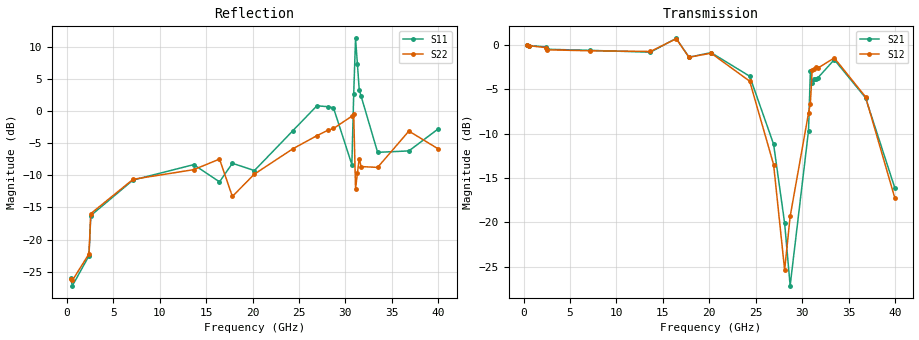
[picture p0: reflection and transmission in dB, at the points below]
! Network Analyzer HP8722ES.07.66: Jul 25, 2000 Serial No. US39175408
! 27 Oct 2004  13:03:41
! Frequency  S11  S21  S12  S22
# HZ  S  DB R  50
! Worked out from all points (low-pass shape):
!   201 points, 400 MHz to 40 GHz, reference 50 ohm
!   highest |S21| = 0.76 dB at 16.44 GHz (marker M1); lowest = -27.1 dB at 28.71 GHz (marker M2)
!   |S21| within 3 dB of the highest: start of sweep to 22.83 GHz; 32.62 GHz to 34.68 GHz (2.058 GHz wide, 6.11 % of centre)
!   lowest |S11| = -27.2 dB at 598 MHz (marker M3), VSWR 1.09, Z = 50.5 - j4.38 ohm
!   |S11| at or under -10 dB: start of sweep to 8.362 GHz; 18.2 GHz to 19.98 GHz (1.779 GHz wide, 9.32 % of centre); 34.47 GHz to 35.31 GHz (841.7 MHz wide, 2.41 % of centre) (the widest 3 of 4)
!   |S22| runs from -26.9 to -0.5 dB; largest |S21 - S12| = 0.27
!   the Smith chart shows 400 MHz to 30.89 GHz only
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4e8  -26.02 -92.3  -0.04 -0.1  -0.03 0.4  -26.09 -90.7
5.98e8  -27.16 -81.1  -0.06 -1.0  -0.07 -0.7  -26.33 -91.0
2.38e9  -22.52 -76.8  -0.20 -9.9  -0.28 -9.8  -22.22 -102.8
2.578e9  -16.26 -78.7  -0.47 -6.7  -0.53 -6.3  -15.96 -90.5
7.132e9  -10.74 -89.8  -0.59 -21.3  -0.64 -22.2  -10.63 -133.1
1.3666e10  -8.35 -77.1  -0.80 -38.7  -0.72 -39.8  -9.13 175.7
1.6438e10  -11.03 -67.2  0.76 -51.1  0.72 -52.4  -7.49 123.7
1.7824e10  -8.14 -51.1  -1.36 -57.5  -1.37 -59.2  -13.29 76.9
2.02e10  -9.27 -0.1  -0.85 -70.4  -0.91 -72.0  -9.82 31.0
2.4358e10  -3.05 18.0  -3.51 -110.5  -4.07 -116.2  -5.87 -55.1
2.6932e10  0.80 1.3  -11.18 -118.6  -13.48 -119.9  -3.85 -70.3
2.812e10  0.65 -10.9  -20.08 -116.8  -25.35 -75.8  -3.00 -89.1
2.8714e10  0.47 -16.9  -27.13 -39.2  -19.32 -4.7  -2.73 -99.7
3.0694e10  -8.35 -41.7  -9.64 0.5  -7.65 -6.1  -0.82 -111.6
3.0892e10  2.60 -15.3  -2.89 -92.8  -6.59 -103.8  -0.53 50.4
3.109e10  11.27 8.8  -4.24 -25.3  -2.76 -33.3  -12.12 144.2
3.1288e10  7.34 -23.0  -3.85 -22.7  -2.68 -31.2  -9.68 179.8
3.1486e10  3.26 -31.0  -3.79 -22.0  -2.49 -31.1  -7.40 -167.7
3.1684e10  2.31 -44.2  -3.71 -25.6  -2.60 -35.6  -8.65 -166.0
3.3466e10  -6.44 -70.0  -1.64 -57.0  -1.45 -65.3  -8.78 -120.7
3.6832e10  -6.22 -9.0  -5.94 -113.2  -5.83 -119.5  -3.14 -127.5
4e10  -2.79 -35.1  -16.15 -83.7  -17.29 -86.7  -5.91 -166.5
